VERSION 5.8 ;
BUSBITCHARS "[]" ;
DIVIDERCHAR "/" ;
UNITS
  DATABASE MICRONS 1000 ;
END UNITS
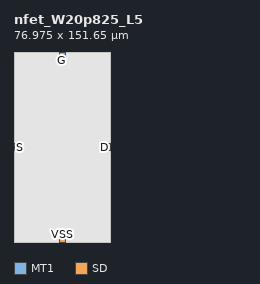
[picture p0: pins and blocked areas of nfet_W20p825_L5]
MACRO nfet_W20p825_L5
  CLASS BLOCK ;
  ORIGIN 0 0 ;
  FOREIGN nfet_W20p825_L5 0 0 ;
  SIZE 76.975 BY 151.65 ;
  SYMMETRY X Y ;
  PIN D
    DIRECTION INOUT ;
    USE SIGNAL ;
    PORT
      LAYER MT1 ;
        RECT 73.9 73.325 76.975 78.325 ;
    END
  END D
  PIN G
    DIRECTION INPUT ;
    USE SIGNAL ;
    PORT
      LAYER MT1 ;
        RECT 36 148.575 41 151.65 ;
    END
  END G
  PIN S
    DIRECTION INOUT ;
    USE SIGNAL ;
    PORT
      LAYER MT1 ;
        RECT 0 73.325 3.075 78.325 ;
    END
  END S
  PIN VSS
    DIRECTION INOUT ;
    USE GROUND ;
    PORT
      LAYER SD ;
        RECT 36 0 41 3.075 ;
    END
  END VSS
  OBS
    LAYER SD ;
      RECT 0 0 76.975 151.65 ;
  END
END nfet_W20p825_L5
END LIBRARY
